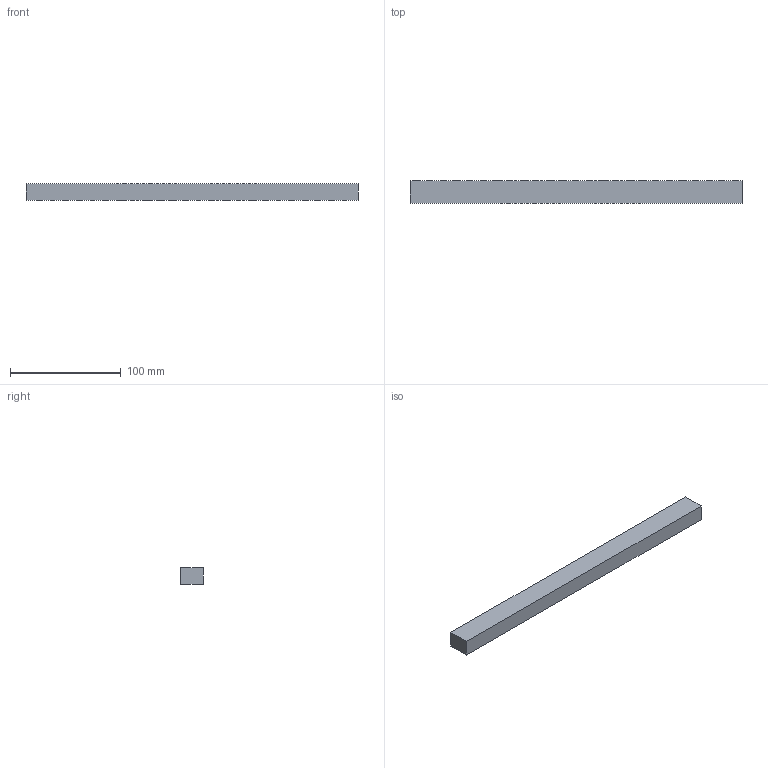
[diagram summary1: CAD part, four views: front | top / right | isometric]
IGES file: header records copied from the file, then geometry measured from it (millimetres).
Start section: START RECORD GO HERE.
Global section: file name: G40515300.igs; native system: DASSAULT SYSTEMES CATIA V5 R20 - www.3ds.com; preprocessor: CATIA Version 5 Release 20 ; author: r.borello; organization: CFTORINO; date: 20190624.150114; units: millimetre
Bounding box: 300 x 20 x 15 mm (x, y, z)
Surface area: 26825.4 mm2 (no closed solid volume)
Topology: 0 solids, 0 shells, 617 faces, 2614 edges, 2368 vertices
Faces by surface type: revolution 538, plane 79
